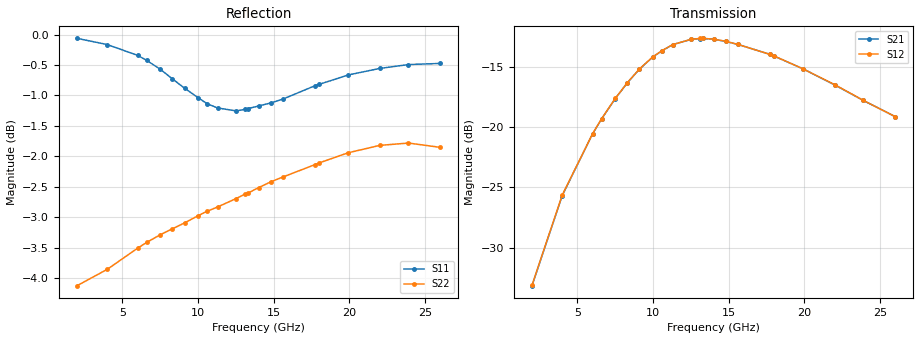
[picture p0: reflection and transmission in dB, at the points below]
! CHUO DENSHI KOGYO Co.,Ltd.
! 26. October 2020
! CKRF7613MM34_RT5880
! N-channel HJ-FET
! Vds = 0 V, Vgs = 0 V
# Hz S  MA  R 50
!	f	S11	S21	S12	S22
!	Hz	MAG	ANG	MAG	ANG	MAG	ANG	MAG	ANG
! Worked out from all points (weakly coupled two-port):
!   241 points, 2 GHz to 26 GHz, reference 50 ohm
!   highest |S21| = -12.65 dB at 13.3 GHz (marker M1); lowest = -33.2 dB at 2 GHz (marker M2)
!   lowest |S11| = -1.3 dB at 12.5 GHz (marker M3), VSWR 13.90, Z = 3.79 + j11.5 ohm
!   |S11| at or under -10 dB: nowhere
!   |S22| runs from -4.1 to -1.8 dB; largest |S21 - S12| = 0.00059
!   S11 on the Smith chart (normalised r, x): 2 GHz: 0.10, -5.14; 6.6 GHz: 0.05, -1.11; 10 GHz: 0.06, -0.26; 13.1 GHz: 0.08, +0.34; 17.7 GHz: 0.14, +1.34; 26 GHz: 4, +11
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2e9  0.9928 -22.0  0.02199 88.4  0.0221 88.7  0.6223 153.1
4e9  0.9812 -45.9  0.052 82.1  0.05231 82.3  0.6419 128.7
6e9  0.9614 -74.2  0.09368 68.5  0.09381 68.6  0.668 107.1
6.6e9  0.9524 -83.9  0.1082 63.4  0.1084 63.5  0.6753 101.1
7.5e9  0.9364 -99.7  0.1312 54.8  0.1314 54.9  0.6852 92.7
8.3e9  0.9197 -115.0  0.1526 46.7  0.1528 46.8  0.6929 85.6
9.1e9  0.9037 -131.4  0.1739 37.5  0.1742 37.5  0.7006 78.9
1e10  0.8875 -151.0  0.1958 26.4  0.196 26.4  0.7103 71.8
1.06e10  0.8774 -164.4  0.2074 18.8  0.2077 18.8  0.7163 67.0
1.13e10  0.8704 -180.0  0.2198 10.0  0.2198 9.9  0.7222 61.8
1.25e10  0.8658 154.1  0.2308 -5.3  0.2311 -5.3  0.7335 53.0
1.31e10  0.8681 141.9  0.2329 -12.7  0.2332 -12.7  0.7398 48.6
1.33e10  0.8696 138.0  0.2331 -15.1  0.2333 -15.1  0.7413 47.2
1.4e10  0.8737 125.0  0.2313 -23.3  0.2316 -23.4  0.749 42.1
1.48e10  0.8789 111.4  0.2266 -32.0  0.2269 -32.0  0.7571 36.3
1.56e10  0.8852 99.4  0.2202 -40.0  0.2203 -40.1  0.7641 30.5
1.77e10  0.9076 73.2  0.2005 -59.5  0.2004 -59.6  0.782 15.8
1.8e10  0.9102 70.0  0.197 -62.2  0.1972 -62.2  0.7847 13.7
1.99e10  0.9264 51.8  0.1745 -78.1  0.1745 -78.1  0.7998 0.6
2.2e10  0.938 35.2  0.1496 -94.3  0.15 -94.5  0.8111 -12.8
2.39e10  0.9449 22.2  0.1289 -108.4  0.129 -108.4  0.8147 -23.9
2.6e10  0.9469 9.3  0.1105 -123.5  0.1105 -123.5  0.8081 -34.7
